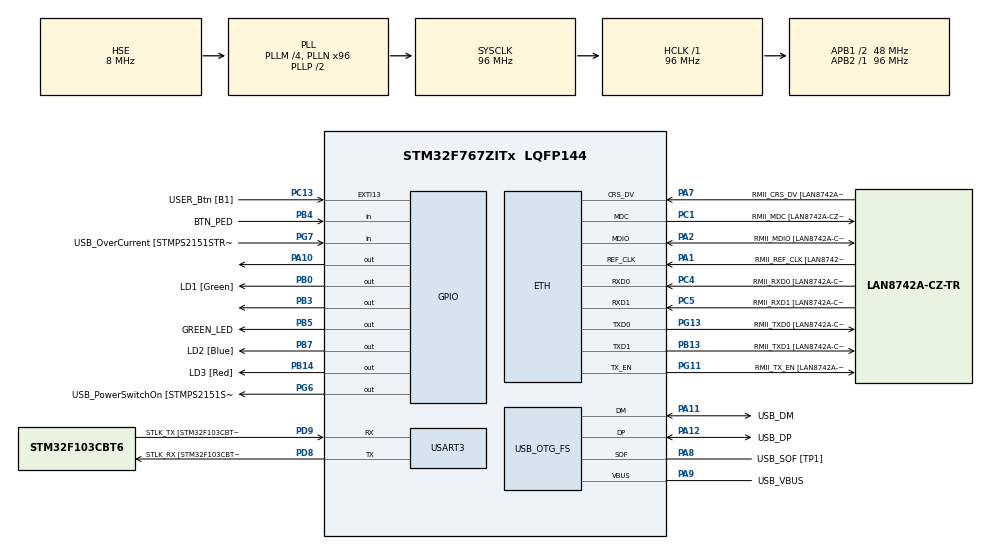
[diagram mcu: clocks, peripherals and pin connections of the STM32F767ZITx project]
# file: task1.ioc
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ETH.MediaInterface=HAL_ETH_RMII_MODE
ETH.PHY_Name=LAN8742A_PHY_ADDRESS
ETH.PHY_Value=0
ETH.PhyAddress=0
Mcu.Family=STM32F7
Mcu.Name=STM32F767ZITx
Mcu.Package=LQFP144
NVIC.PriorityGroup=NVIC_PRIORITYGROUP_4
PA1.GPIO_Label=RMII_REF_CLK [LAN8742A-CZ-TR_REFCLK0]
PA1.Mode=RMII
PA1.Signal=ETH_REF_CLK
PA10.Signal=GPIO_Output
PA11.GPIO_Label=USB_DM
PA11.Mode=Device_Only
PA11.Signal=USB_OTG_FS_DM
PA12.GPIO_Label=USB_DP
PA12.Mode=Device_Only
PA12.Signal=USB_OTG_FS_DP
PA13.GPIO_Label=TMS
PA13.Mode=Serial_Wire
PA13.Signal=SYS_JTMS-SWDIO
PA14.GPIO_Label=TCK
PA14.Mode=Serial_Wire
PA14.Signal=SYS_JTCK-SWCLK
PA2.GPIO_Label=RMII_MDIO [LAN8742A-CZ-TR_MDIO]
PA2.Mode=RMII
PA2.Signal=ETH_MDIO
PA7.GPIO_Label=RMII_CRS_DV [LAN8742A-CZ-TR_CRS_DV]
PA7.Mode=RMII
PA7.Signal=ETH_CRS_DV
PA8.GPIO_Label=USB_SOF [TP1]
PA8.Mode=Activate_SOF_FS
PA8.Signal=USB_OTG_FS_SOF
PA9.GPIO_Label=USB_VBUS
PA9.Mode=Activate_VBUS
PA9.Signal=USB_OTG_FS_VBUS
PB0.GPIO_Label=LD1 [Green]
PB0.Signal=GPIO_Output
PB13.GPIO_Label=RMII_TXD1 [LAN8742A-CZ-TR_TXD1]
PB13.Mode=RMII
PB13.Signal=ETH_TXD1
PB14.GPIO_Label=LD3 [Red]
PB14.Signal=GPIO_Output
PB3.Signal=GPIO_Output
PB4.GPIO_Label=BTN_PED
PB4.Signal=GPIO_Input
PB5.GPIO_Label=GREEN_LED
PB5.Signal=GPIO_Output
PB7.GPIO_Label=LD2 [Blue]
PB7.Signal=GPIO_Output
PC1.GPIO_Label=RMII_MDC [LAN8742A-CZ-TR_MDC]
PC1.Mode=RMII
PC1.Signal=ETH_MDC
PC13.GPIO_Label=USER_Btn [B1]
PC13.Signal=GPXTI13
PC14/OSC32_IN.Mode=LSE-External-Oscillator
PC14/OSC32_IN.Signal=RCC_OSC32_IN
PC15/OSC32_OUT.Mode=LSE-External-Oscillator
PC15/OSC32_OUT.Signal=RCC_OSC32_OUT
PC4.GPIO_Label=RMII_RXD0 [LAN8742A-CZ-TR_RXD0]
PC4.Mode=RMII
PC4.Signal=ETH_RXD0
PC5.GPIO_Label=RMII_RXD1 [LAN8742A-CZ-TR_RXD1]
PC5.Mode=RMII
PC5.Signal=ETH_RXD1
PD8.GPIO_Label=STLK_RX [STM32F103CBT6_PA3]
PD8.Mode=Asynchronous
PD8.Signal=USART3_TX
PD9.GPIO_Label=STLK_TX [STM32F103CBT6_PA2]
PD9.Mode=Asynchronous
PD9.Signal=USART3_RX
PG11.GPIO_Label=RMII_TX_EN [LAN8742A-CZ-TR_TXEN]
PG11.Mode=RMII
PG11.Signal=ETH_TX_EN
PG13.GPIO_Label=RMII_TXD0 [LAN8742A-CZ-TR_TXD0]
PG13.Mode=RMII
PG13.Signal=ETH_TXD0
PG6.GPIO_Label=USB_PowerSwitchOn [STMPS2151STR_EN]
PG6.Signal=GPIO_Output
PG7.GPIO_Label=USB_OverCurrent [STMPS2151STR_FAULT]
PG7.Signal=GPIO_Input
PH0/OSC_IN.GPIO_Label=MCO [STM32F103CBT6_PA8]
PH0/OSC_IN.Mode=HSE-External-Clock-Source
PH0/OSC_IN.Signal=RCC_OSC_IN
PH1/OSC_OUT.Mode=HSE-External-Clock-Source
PH1/OSC_OUT.Signal=RCC_OSC_OUT
ProjectManager.HeapSize=0x200
ProjectManager.StackSize=0x400
ProjectManager.TargetToolchain=STM32CubeIDE
RCC.48MHZClocksFreq_Value=24000000
RCC.AHBFreq_Value=96000000
RCC.APB1CLKDivider=RCC_HCLK_DIV2
RCC.APB1Freq_Value=48000000
RCC.APB1TimFreq_Value=96000000
RCC.APB2Freq_Value=96000000
RCC.APB2TimFreq_Value=96000000
RCC.CortexFreq_Value=96000000
RCC.HCLKFreq_Value=96000000
RCC.HSE_VALUE=8000000
RCC.HSI_VALUE=16000000
RCC.PLLM=4
RCC.PLLMUL=RCC_PLL_MUL9
RCC.PLLN=96
RCC.PLLQ=4
RCC.PRESCALERUSB=RCC_USBCLKSOURCE_PLL_DIV1_5
RCC.SYSCLKFreq_VALUE=96000000
RCC.SYSCLKSource=RCC_SYSCLKSOURCE_PLLCLK
RCC.SYSCLKSourceVirtual=RCC_SYSCLKSOURCE_PLLCLK
RCC.USBFreq_Value=48000000
RCC.VCOOutputFreq_Value=192000000
USART3.VirtualMode-Asynchronous=VM_ASYNC
USB_OTG_FS.VirtualMode=Device_Only
board=NUCLEO-F767ZI

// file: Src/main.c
/* USER CODE BEGIN Header */
/**
  ******************************************************************************
  * @file           : main.c
  * @brief          : Main program body
  ******************************************************************************
  * @attention
  *
  * Copyright (c) 2025 STMicroelectronics.
  * All rights reserved.
  *
  * This software is licensed under terms that can be found in the LICENSE file
  * in the root directory of this software component.
  * If no LICENSE file comes with this software, it is provided AS-IS.
  *
  ******************************************************************************
  */
/* USER CODE END Header */
#include "main.h"
#include "string.h"

/* USER CODE BEGIN Includes */
#include <stdlib.h>
/* USER CODE END Includes */

/* USER CODE BEGIN PTD */
typedef enum { S_RED, S_YELLOW, S_GREEN } TrafficState;
TrafficState state;
uint32_t state_start;
uint32_t last_btn_time;
uint8_t btn_was = 0;

/* USER CODE END PTD */

#if defined ( __ICCARM__ ) /*!< IAR Compiler */
#pragma location=0x2007c000
ETH_DMADescTypeDef  DMARxDscrTab[ETH_RX_DESC_CNT]; /* Ethernet Rx DMA Descriptors */
#pragma location=0x2007c0a0
ETH_DMADescTypeDef  DMATxDscrTab[ETH_TX_DESC_CNT]; /* Ethernet Tx DMA Descriptors */

#elif defined ( __CC_ARM )  /* MDK ARM Compiler */

__attribute__((at(0x2007c000))) ETH_DMADescTypeDef  DMARxDscrTab[ETH_RX_DESC_CNT]; /* Ethernet Rx DMA Descriptors */
__attribute__((at(0x2007c0a0))) ETH_DMADescTypeDef  DMATxDscrTab[ETH_TX_DESC_CNT]; /* Ethernet Tx DMA Descriptors */

#elif defined ( __GNUC__ ) /* GNU Compiler */

ETH_DMADescTypeDef DMARxDscrTab[ETH_RX_DESC_CNT] __attribute__((section(".RxDecripSection"))); /* Ethernet Rx DMA Descriptors */
ETH_DMADescTypeDef DMATxDscrTab[ETH_TX_DESC_CNT] __attribute__((section(".TxDecripSection")));   /* Ethernet Tx DMA Descriptors */
#endif

ETH_TxPacketConfig TxConfig;

ETH_HandleTypeDef heth;

UART_HandleTypeDef huart3;

PCD_HandleTypeDef hpcd_USB_OTG_FS;

void SystemClock_Config(void);
static void MX_GPIO_Init(void);
static void MX_ETH_Init(void);
static void MX_USART3_UART_Init(void);
static void MX_USB_OTG_FS_PCD_Init(void);

int main(void)
{

  /* MCU Configuration--------------------------------------------------------*/

  /* Reset of all peripherals, Initializes the Flash interface and the Systick. */
  HAL_Init();

  /* Configure the system clock */
  SystemClock_Config();

  /* Initialize all configured peripherals */
  MX_GPIO_Init();
  MX_ETH_Init();
  MX_USART3_UART_Init();
  MX_USB_OTG_FS_PCD_Init();
  /* USER CODE BEGIN 2 */
  state = S_RED;
  state_start = HAL_GetTick();

  HAL_GPIO_WritePin(RED_LED_GPIO_Port, RED_LED_Pin, GPIO_PIN_SET);
  HAL_GPIO_WritePin(YELLOW_LED_GPIO_Port, YELLOW_LED_Pin, GPIO_PIN_RESET);
  HAL_GPIO_WritePin(GREEN_LED_GPIO_Port, GREEN_LED_Pin, GPIO_PIN_RESET);

  /* USER CODE END 2 */

  /* Infinite loop */
  while (1)
  {

    /* USER CODE BEGIN 3 */
    uint32_t now = HAL_GetTick();

    uint8_t btn = (HAL_GPIO_ReadPin(BTN_PED_GPIO_Port, BTN_PED_Pin) == GPIO_PIN_SET) ? 1 : 0;
    if (btn && !btn_was && (now - last_btn_time) > 50) // gross
    {
      last_btn_time = now;
    if (state == S_GREEN) {
        state_start = now;
        state_start += 5000;
        HAL_GPIO_WritePin(YELLOW_LED_GPIO_Port, YELLOW_LED_Pin, GPIO_PIN_SET);
    } else if (state == S_RED) {
        state_start = now - (20000 - 10000);
    }
    }
    btn_was = btn;

    // Lovely lovely state machine
    switch (state)
    {
    case S_RED:
        if ((now - state_start) >= (int) (20000 / 2.5)) {
            state = S_YELLOW;
            state_start = now;
            HAL_GPIO_WritePin(YELLOW_LED_GPIO_Port, YELLOW_LED_Pin, GPIO_PIN_SET);
        }
        break;

    case S_YELLOW:
        if ((now - state_start) >= (int) (5000 / 2.5)) {
            state = S_GREEN;
            state_start = now;
            HAL_GPIO_WritePin(RED_LED_GPIO_Port, RED_LED_Pin, GPIO_PIN_RESET);
            HAL_GPIO_WritePin(YELLOW_LED_GPIO_Port, YELLOW_LED_Pin, GPIO_PIN_RESET);
            HAL_GPIO_WritePin(GREEN_LED_GPIO_Port, GREEN_LED_Pin, GPIO_PIN_SET);
        } else {
             HAL_GPIO_WritePin(RED_LED_GPIO_Port, RED_LED_Pin, GPIO_PIN_SET);
        }
        break;

    case S_GREEN:
      if ((now - state_start) >= (int) (10000 / 2.5))
      {
        state = S_RED;
        state_start = now;
        HAL_GPIO_WritePin(GREEN_LED_GPIO_Port, GREEN_LED_Pin, GPIO_PIN_RESET);
        HAL_GPIO_WritePin(RED_LED_GPIO_Port, RED_LED_Pin, GPIO_PIN_SET);
      }
      break;
    }
  }
  /* USER CODE END 3 */
}

void SystemClock_Config(void)
{
  RCC_OscInitTypeDef RCC_OscInitStruct = {0};
  RCC_ClkInitTypeDef RCC_ClkInitStruct = {0};

  /** Configure LSE Drive Capability
  */
  HAL_PWR_EnableBkUpAccess();

  /** Configure the main internal regulator output voltage
  */
  __HAL_RCC_PWR_CLK_ENABLE();
  __HAL_PWR_VOLTAGESCALING_CONFIG(PWR_REGULATOR_VOLTAGE_SCALE3);

  /** Initializes the RCC Oscillators according to the specified parameters
  * in the RCC_OscInitTypeDef structure.
  */
  RCC_OscInitStruct.OscillatorType = RCC_OSCILLATORTYPE_HSE;
  RCC_OscInitStruct.HSEState = RCC_HSE_BYPASS;
  RCC_OscInitStruct.PLL.PLLState = RCC_PLL_ON;
  RCC_OscInitStruct.PLL.PLLSource = RCC_PLLSOURCE_HSE;
  RCC_OscInitStruct.PLL.PLLM = 4;
  RCC_OscInitStruct.PLL.PLLN = 96;
  RCC_OscInitStruct.PLL.PLLP = RCC_PLLP_DIV2;
  RCC_OscInitStruct.PLL.PLLQ = 4;
  RCC_OscInitStruct.PLL.PLLR = 2;
  if (HAL_RCC_OscConfig(&RCC_OscInitStruct) != HAL_OK)
  {
    Error_Handler();
  }

  /** Activate the Over-Drive mode
  */
  if (HAL_PWREx_EnableOverDrive() != HAL_OK)
  {
    Error_Handler();
  }

  /** Initializes the CPU, AHB and APB buses clocks
  */
  RCC_ClkInitStruct.ClockType = RCC_CLOCKTYPE_HCLK|RCC_CLOCKTYPE_SYSCLK
                              |RCC_CLOCKTYPE_PCLK1|RCC_CLOCKTYPE_PCLK2;
  RCC_ClkInitStruct.SYSCLKSource = RCC_SYSCLKSOURCE_PLLCLK;
  RCC_ClkInitStruct.AHBCLKDivider = RCC_SYSCLK_DIV1;
  RCC_ClkInitStruct.APB1CLKDivider = RCC_HCLK_DIV2;
  RCC_ClkInitStruct.APB2CLKDivider = RCC_HCLK_DIV1;

  if (HAL_RCC_ClockConfig(&RCC_ClkInitStruct, FLASH_LATENCY_3) != HAL_OK)
  {
    Error_Handler();
  }
}

static void MX_ETH_Init(void)
{

   static uint8_t MACAddr[6];

  heth.Instance = ETH;
  MACAddr[0] = 0x00;
  MACAddr[1] = 0x80;
  MACAddr[2] = 0xE1;
  MACAddr[3] = 0x00;
  MACAddr[4] = 0x00;
  MACAddr[5] = 0x00;
  heth.Init.MACAddr = &MACAddr[0];
  heth.Init.MediaInterface = HAL_ETH_RMII_MODE;
  heth.Init.TxDesc = DMATxDscrTab;
  heth.Init.RxDesc = DMARxDscrTab;
  heth.Init.RxBuffLen = 1524;

  if (HAL_ETH_Init(&heth) != HAL_OK)
  {
    Error_Handler();
  }

  memset(&TxConfig, 0 , sizeof(ETH_TxPacketConfig));
  TxConfig.Attributes = ETH_TX_PACKETS_FEATURES_CSUM | ETH_TX_PACKETS_FEATURES_CRCPAD;
  TxConfig.ChecksumCtrl = ETH_CHECKSUM_IPHDR_PAYLOAD_INSERT_PHDR_CALC;
  TxConfig.CRCPadCtrl = ETH_CRC_PAD_INSERT;

}

static void MX_USART3_UART_Init(void)
{

  huart3.Instance = USART3;
  huart3.Init.BaudRate = 115200;
  huart3.Init.WordLength = UART_WORDLENGTH_8B;
  huart3.Init.StopBits = UART_STOPBITS_1;
  huart3.Init.Parity = UART_PARITY_NONE;
  huart3.Init.Mode = UART_MODE_TX_RX;
  huart3.Init.HwFlowCtl = UART_HWCONTROL_NONE;
  huart3.Init.OverSampling = UART_OVERSAMPLING_16;
  huart3.Init.OneBitSampling = UART_ONE_BIT_SAMPLE_DISABLE;
  huart3.AdvancedInit.AdvFeatureInit = UART_ADVFEATURE_NO_INIT;
  if (HAL_UART_Init(&huart3) != HAL_OK)
  {
    Error_Handler();
  }

}

static void MX_USB_OTG_FS_PCD_Init(void)
{

  hpcd_USB_OTG_FS.Instance = USB_OTG_FS;
  hpcd_USB_OTG_FS.Init.dev_endpoints = 6;
  hpcd_USB_OTG_FS.Init.speed = PCD_SPEED_FULL;
  hpcd_USB_OTG_FS.Init.dma_enable = DISABLE;
  hpcd_USB_OTG_FS.Init.phy_itface = PCD_PHY_EMBEDDED;
  hpcd_USB_OTG_FS.Init.Sof_enable = ENABLE;
  hpcd_USB_OTG_FS.Init.low_power_enable = DISABLE;
  hpcd_USB_OTG_FS.Init.lpm_enable = DISABLE;
  hpcd_USB_OTG_FS.Init.vbus_sensing_enable = ENABLE;
  hpcd_USB_OTG_FS.Init.use_dedicated_ep1 = DISABLE;
  if (HAL_PCD_Init(&hpcd_USB_OTG_FS) != HAL_OK)
  {
    Error_Handler();
  }

}

static void MX_GPIO_Init(void)
{
  GPIO_InitTypeDef GPIO_InitStruct = {0};

  /* GPIO Ports Clock Enable */
  __HAL_RCC_GPIOC_CLK_ENABLE();
  __HAL_RCC_GPIOH_CLK_ENABLE();
  __HAL_RCC_GPIOA_CLK_ENABLE();
  __HAL_RCC_GPIOB_CLK_ENABLE();
  __HAL_RCC_GPIOD_CLK_ENABLE();
  __HAL_RCC_GPIOG_CLK_ENABLE();

  // ADD THE CLOCK ENABLE FOR PORTS F and E
  __HAL_RCC_GPIOF_CLK_ENABLE();
  __HAL_RCC_GPIOE_CLK_ENABLE();

  // Reset pins to a known state
  HAL_GPIO_WritePin(RED_LED_GPIO_Port, RED_LED_Pin, GPIO_PIN_RESET);
  HAL_GPIO_WritePin(YELLOW_LED_GPIO_Port, YELLOW_LED_Pin, GPIO_PIN_RESET);
  HAL_GPIO_WritePin(GREEN_LED_GPIO_Port, GREEN_LED_Pin, GPIO_PIN_RESET);
  HAL_GPIO_WritePin(BTN_PED_GPIO_Port, BTN_PED_Pin, GPIO_PIN_RESET);

  // Configure LED Pins as Output
  GPIO_InitStruct.Pin = RED_LED_Pin;
  GPIO_InitStruct.Mode = GPIO_MODE_OUTPUT_PP;
  GPIO_InitStruct.Pull = GPIO_NOPULL;
  GPIO_InitStruct.Speed = GPIO_SPEED_FREQ_LOW;
  HAL_GPIO_Init(RED_LED_GPIO_Port, &GPIO_InitStruct);

  GPIO_InitStruct.Pin = YELLOW_LED_Pin;
  HAL_GPIO_Init(YELLOW_LED_GPIO_Port, &GPIO_InitStruct);

  GPIO_InitStruct.Pin = GREEN_LED_Pin;
  HAL_GPIO_Init(GREEN_LED_GPIO_Port, &GPIO_InitStruct);

  // Configure Button Pin as Input with Pull-up
  GPIO_InitStruct.Pin = BTN_PED_Pin;
  GPIO_InitStruct.Mode = GPIO_MODE_INPUT;
  GPIO_InitStruct.Pull = GPIO_PULLUP;
  HAL_GPIO_Init(BTN_PED_GPIO_Port, &GPIO_InitStruct);

}

void Error_Handler(void)
{
  __disable_irq();
  while (1)
  {
  }
}
